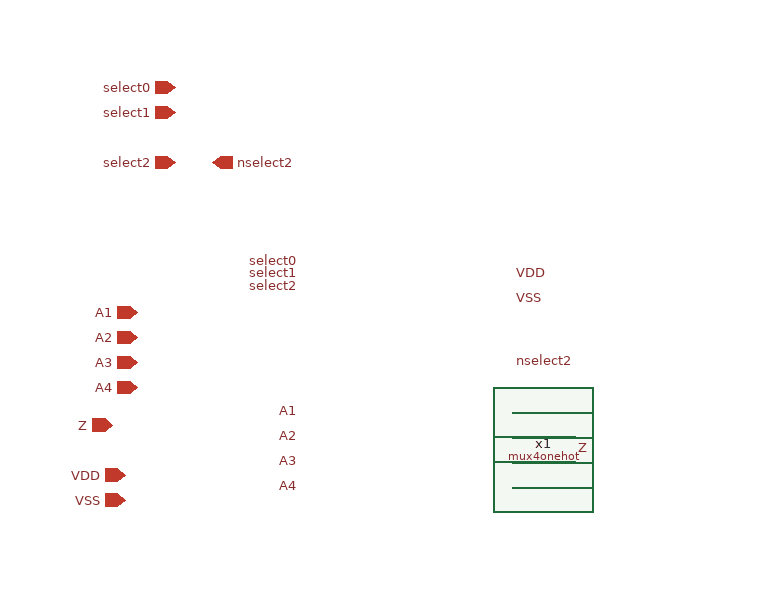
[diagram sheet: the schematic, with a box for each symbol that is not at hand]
v {xschem version=3.4.5 file_version=1.2
}
G {}
K {}
V {}
S {}
E {}
N 340 -170 390 -170 {
lab=Z}
N 390 -170 390 -110 {
lab=Z}
N 340 -110 390 -110 {
lab=Z}
N 340 -130 390 -130 {
lab=Z}
N 340 -150 390 -150 {
lab=Z}
C {/home/ttuser/vmswap/analogmuxkit/xschem/mux4onehot.sym} 150 -90 0 0 {name=x1}
C {devices/lab_pin.sym} 170 -290 0 0 {name=p1 lab=select0}
C {devices/lab_pin.sym} 170 -280 0 0 {name=p2 lab=select1}
C {devices/lab_pin.sym} 170 -270 0 0 {name=p3 lab=select2}
C {devices/lab_pin.sym} 170 -170 2 1 {name=p4 lab=A1}
C {devices/lab_pin.sym} 170 -150 2 1 {name=p5 lab=A2}
C {devices/lab_pin.sym} 170 -130 2 1 {name=p6 lab=A3}
C {devices/lab_pin.sym} 170 -110 2 1 {name=p7 lab=A4}
C {devices/lab_pin.sym} 390 -140 0 1 {name=p11 lab=Z}
C {devices/lab_pin.sym} 340 -210 0 1 {name=p12 lab=nselect2}
C {devices/lab_pin.sym} 340 -280 2 0 {name=p13 lab=VDD}
C {devices/lab_pin.sym} 340 -260 2 0 {name=p14 lab=VSS}
C {devices/ipin.sym} 70 -430 0 0 {name=p15 lab=select0}
C {devices/ipin.sym} 70 -410 0 0 {name=p16 lab=select1}
C {devices/ipin.sym} 70 -370 0 0 {name=p17 lab=select2}
C {devices/opin.sym} 100 -370 0 0 {name=p18 lab=nselect2}
C {devices/iopin.sym} 40 -250 2 0 {name=p8 lab=A1}
C {devices/iopin.sym} 40 -230 2 0 {name=p9 lab=A2}
C {devices/iopin.sym} 40 -210 2 0 {name=p10 lab=A3}
C {devices/iopin.sym} 40 -190 2 0 {name=p19 lab=A4}
C {devices/iopin.sym} 20 -160 0 0 {name=p20 lab=Z}
C {devices/ipin.sym} 30 -120 0 0 {name=p21 lab=VDD}
C {devices/ipin.sym} 30 -100 0 0 {name=p22 lab=VSS}
